VERSION 5.8 ;
BUSBITCHARS "[]" ;
DIVIDERCHAR "/" ;

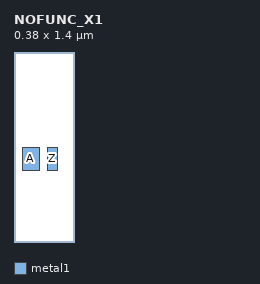
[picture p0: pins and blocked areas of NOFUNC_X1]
MACRO NOFUNC_X1
  CLASS CORE ;
  ORIGIN 0 0 ;
  FOREIGN NOFUNC_X1 0 0 ;
  SIZE 0.38 BY 1.4 ;
  SYMMETRY X Y ;
  SITE FreePDK45_38x28_10R_NP_162NW_34O ;
  PIN A
    DIRECTION INPUT ;
    USE SIGNAL ;
    PORT
      LAYER metal1 ;
        RECT 0.06 0.525 0.19 0.7 ;
    END
  END A
  PIN Z
    DIRECTION OUTPUT ;
    USE SIGNAL ;
    PORT
      LAYER metal1 ;
        RECT 0.25 0.525 0.32 0.7 ;
    END
  END Z
END NOFUNC_X1

END LIBRARY
